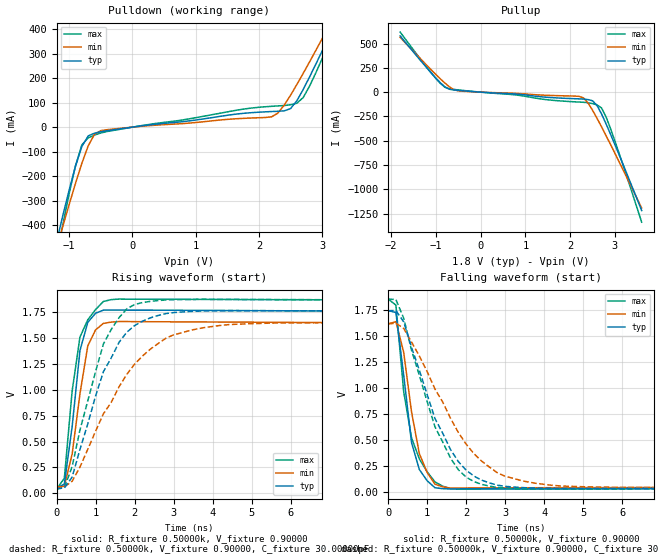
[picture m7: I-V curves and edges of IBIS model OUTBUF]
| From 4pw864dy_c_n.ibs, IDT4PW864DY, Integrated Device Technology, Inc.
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|   Model OUTBUF
[Model]   OUTBUF
Model_type   Output
Polarity   Inverting
Vmeas =  0.90000V
C_comp   6.50000pF   5.40000pF   8.10000pF
[Temperature Range]   25.00000   0.11000k   0.000
[Voltage Range]   1.80000V   1.70000V   1.90000V
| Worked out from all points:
|   slope of the pulldown table from 0 to 0.27 V, typ, clamps not added: 29.7 ohm
|   slope of the pullup table from 0 to 0.27 V, typ, clamps not added: 35.5 ohm
|   rising waveform, R_fixture 0.50000k, V_fixture 0.90000: 20-80 % time 319ps typ, 359ps min, 336ps max; typ from 0.047 V to 1.76 V
|   rising waveform, R_fixture 0.50000k, V_fixture 0.90000, C_fixture 30.00000pF: 20-80 % time 970ps typ, 1.46ns min, 802ps max; typ from 0.047 V to 1.76 V
|   falling waveform, R_fixture 0.50000k, V_fixture 0.90000: 20-80 % time 368ps typ, 398ps min, 449ps max; typ from 1.74 V to 0.033 V
|   falling waveform, R_fixture 0.50000k, V_fixture 0.90000, C_fixture 30.00000pF: 20-80 % time 1.06ns typ, 1.42ns min, 989ps max; typ from 1.74 V to 0.033 V
[Pulldown]
| voltage   I(typ)   I(min)   I(max)
-1.8V     -1.143A    -1.055A    -1.369A
-1.2V     -468.2mA   -494.8mA   -530.4mA
-1.1V     -360.2mA   -404.2mA   -397.3mA
-900mV    -159.4mA   -229.2mA   -157.3mA
-700mV    -35.9mA    -76.96mA   -43.81mA
-500mV    -18.76mA   -14.22mA   -23.72mA
2.2V      63.59mA    42.02mA    84.92mA
2.5V      75.54mA    130.3mA    91.16mA
2.7V      153.8mA    219.5mA    120.8mA
3.1V      365.5mA    409.3mA    339mA
3.2V      420.6mA    457.7mA    399.3mA
3.6V      644mA      653.4mA    645.2mA
[Pullup]
| voltage   I(typ)   I(min)   I(max)
-1.8V     578.2mA    563.7mA    617.9mA
-1.1V     194.8mA    226.9mA    195.6mA
-800mV    54.3mA     93.38mA    50.68mA
-500mV    17.9mA     13.27mA    22.79mA
2.2V      -69.17mA   -43.15mA   -102.1mA
2.3V      -71.47mA   -59.74mA   -104.5mA
2.5V      -88.72mA   -184.8mA   -118.1mA
2.6V      -135.7mA   -267.6mA   -130.7mA
2.7V      -221.9mA   -354.7mA   -161.6mA
2.8V      -322.5mA   -444.3mA   -250.7mA
3V        -538.4mA   -627.7mA   -501mA
3.6V      -1.218A    -1.192A    -1.338A
[Ramp]
| variable   typ   min   max
dV/dt_r   1.02780/0.32747n   0.95220/0.39005n   1.09980/0.36337n
dV/dt_f   1.03937/0.39404n   0.96796/0.44641n   1.10212/0.48455n
R_load = 0.50000k
[Rising Waveform]
R_fixture = 0.50000k
V_fixture = 0.90000
V_fixture_min = 0.85000
V_fixture_max = 0.95000
| time   V(typ)   V(min)   V(max)
0s        46.99mV    63.91mV    40.55mV
200ps     90.87mV    68.86mV    145.7mV
400ps     645.4mV    380mV      989.5mV
600ps     1.379V     962mV      1.509V
800ps     1.651V     1.424V     1.676V
1ns       1.739V     1.579V     1.775V
1.2ns     1.769V     1.641V     1.853V
1.4ns     1.77V      1.653V     1.871V
1.6ns     1.77V      1.659V     1.876V
10ns      1.757V     1.645V     1.867V
[Rising Waveform]
R_fixture = 0.50000k
V_fixture = 0.90000
V_fixture_min = 0.85000
V_fixture_max = 0.95000
C_fixture = 30.00000pF
| time   V(typ)   V(min)   V(max)
0s        46.99mV    63.91mV    40.55mV
200ps     51.46mV    62.56mV    56.01mV
400ps     156.8mV    116.8mV    258.5mV
600ps     425.2mV    254.2mV    612.4mV
1.2ns     1.175V     768mV      1.442V
1.6ns     1.458V     1.029V     1.696V
2ns       1.621V     1.248V     1.823V
2.8ns     1.736V     1.498V     1.867V
4.2ns     1.764V     1.622V     1.873V
10ns      1.758V     1.645V     1.867V
[Falling Waveform]
R_fixture = 0.50000k
V_fixture = 0.90000
V_fixture_min = 0.85000
V_fixture_max = 0.95000
| time   V(typ)   V(min)   V(max)
0s        1.744V     1.617V     1.856V
200ps     1.726V     1.639V     1.798V
400ps     1.121V     1.342V     961.8mV
600ps     473.6mV    769.5mV    520.3mV
800ps     214.3mV    368mV      317mV
1ns       106.2mV    186.1mV    193.3mV
1.2ns     39.23mV    73.02mV    95.1mV
1.4ns     29.98mV    47.44mV    54.51mV
1.8ns     28.29mV    35.25mV    25.41mV
10ns      33.42mV    42.68mV    31.14mV
[Falling Waveform]
R_fixture = 0.50000k
V_fixture = 0.90000
V_fixture_min = 0.85000
V_fixture_max = 0.95000
C_fixture = 30.00000pF
| time   V(typ)   V(min)   V(max)
0s        1.744V     1.617V     1.856V
200ps     1.746V     1.623V     1.851V
400ps     1.637V     1.573V     1.671V
600ps     1.392V     1.442V     1.364V
1.2ns     706mV      990.1mV    625.9mV
1.8ns     289.9mV    570.4mV    211.9mV
2.2ns     150.6mV    366.3mV    98mV
3ns       52.35mV    148.9mV    35.86mV
4.2ns     32.66mV    62.86mV    28.21mV
10ns      33.25mV    42.47mV    30.94mV
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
